VERSION 5.7 ;
  NOWIREEXTENSIONATPIN ON ;
  DIVIDERCHAR "/" ;
  BUSBITCHARS "[]" ;
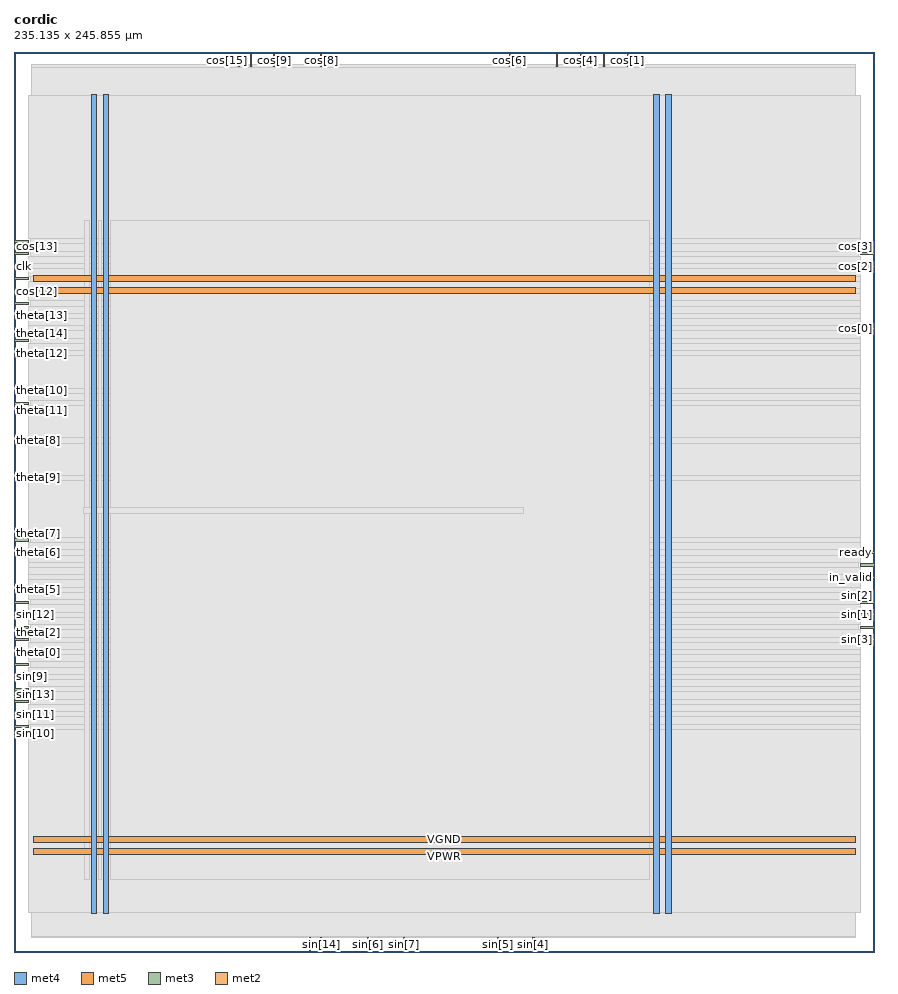
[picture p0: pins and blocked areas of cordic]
MACRO cordic
  CLASS BLOCK ;
  FOREIGN cordic ;
  ORIGIN 0.000 0.000 ;
  SIZE 235.135 BY 245.855 ;
  PIN VGND
    DIRECTION INOUT ;
    USE GROUND ;
    PORT
      LAYER met4 ;
        RECT 24.340 10.640 25.940 234.160 ;
    END
    PORT
      LAYER met4 ;
        RECT 177.940 10.640 179.540 234.160 ;
    END
    PORT
      LAYER met5 ;
        RECT 5.280 30.030 229.780 31.630 ;
    END
    PORT
      LAYER met5 ;
        RECT 5.280 183.210 229.780 184.810 ;
    END
  END VGND
  PIN VPWR
    DIRECTION INOUT ;
    USE POWER ;
    PORT
      LAYER met4 ;
        RECT 21.040 10.640 22.640 234.160 ;
    END
    PORT
      LAYER met4 ;
        RECT 174.640 10.640 176.240 234.160 ;
    END
    PORT
      LAYER met5 ;
        RECT 5.280 26.730 229.780 28.330 ;
    END
    PORT
      LAYER met5 ;
        RECT 5.280 179.910 229.780 181.510 ;
    END
  END VPWR
  PIN clk
    DIRECTION INPUT ;
    USE SIGNAL ;
    ANTENNAGATEAREA 0.852000 ;
    PORT
      LAYER met3 ;
        RECT 0.000 187.040 4.000 187.640 ;
    END
  END clk
  PIN cos[0]
    DIRECTION OUTPUT ;
    USE SIGNAL ;
    ANTENNADIFFAREA 0.795200 ;
    PORT
      LAYER met3 ;
        RECT 231.135 170.040 235.135 170.640 ;
    END
  END cos[0]
  PIN cos[10]
    DIRECTION OUTPUT ;
    USE SIGNAL ;
    ANTENNADIFFAREA 0.795200 ;
    PORT
      LAYER met2 ;
        RECT 64.490 241.855 64.770 245.855 ;
    END
  END cos[10]
  PIN cos[11]
    DIRECTION OUTPUT ;
    USE SIGNAL ;
    ANTENNADIFFAREA 0.795200 ;
    PORT
      LAYER met2 ;
        RECT 61.270 241.855 61.550 245.855 ;
    END
  END cos[11]
  PIN cos[12]
    DIRECTION OUTPUT ;
    USE SIGNAL ;
    ANTENNADIFFAREA 0.795200 ;
    PORT
      LAYER met3 ;
        RECT 0.000 180.240 4.000 180.840 ;
    END
  END cos[12]
  PIN cos[13]
    DIRECTION OUTPUT ;
    USE SIGNAL ;
    ANTENNADIFFAREA 0.795200 ;
    PORT
      LAYER met3 ;
        RECT 0.000 190.440 4.000 191.040 ;
    END
  END cos[13]
  PIN cos[14]
    DIRECTION OUTPUT ;
    USE SIGNAL ;
    ANTENNADIFFAREA 0.795200 ;
    PORT
      LAYER met3 ;
        RECT 0.000 193.840 4.000 194.440 ;
    END
  END cos[14]
  PIN cos[15]
    DIRECTION OUTPUT ;
    USE SIGNAL ;
    ANTENNADIFFAREA 0.795200 ;
    PORT
      LAYER met2 ;
        RECT 58.050 241.855 58.330 245.855 ;
    END
  END cos[15]
  PIN cos[1]
    DIRECTION OUTPUT ;
    USE SIGNAL ;
    ANTENNADIFFAREA 0.795200 ;
    PORT
      LAYER met2 ;
        RECT 167.530 241.855 167.810 245.855 ;
    END
  END cos[1]
  PIN cos[2]
    DIRECTION OUTPUT ;
    USE SIGNAL ;
    ANTENNADIFFAREA 0.795200 ;
    PORT
      LAYER met3 ;
        RECT 231.135 187.040 235.135 187.640 ;
    END
  END cos[2]
  PIN cos[3]
    DIRECTION OUTPUT ;
    USE SIGNAL ;
    ANTENNADIFFAREA 0.795200 ;
    PORT
      LAYER met3 ;
        RECT 231.135 190.440 235.135 191.040 ;
    END
  END cos[3]
  PIN cos[4]
    DIRECTION OUTPUT ;
    USE SIGNAL ;
    ANTENNADIFFAREA 0.795200 ;
    PORT
      LAYER met2 ;
        RECT 154.650 241.855 154.930 245.855 ;
    END
  END cos[4]
  PIN cos[5]
    DIRECTION OUTPUT ;
    USE SIGNAL ;
    ANTENNADIFFAREA 0.795200 ;
    PORT
      LAYER met2 ;
        RECT 161.090 241.855 161.370 245.855 ;
    END
  END cos[5]
  PIN cos[6]
    DIRECTION OUTPUT ;
    USE SIGNAL ;
    ANTENNADIFFAREA 0.795200 ;
    PORT
      LAYER met2 ;
        RECT 135.330 241.855 135.610 245.855 ;
    END
  END cos[6]
  PIN cos[7]
    DIRECTION OUTPUT ;
    USE SIGNAL ;
    ANTENNADIFFAREA 0.795200 ;
    PORT
      LAYER met2 ;
        RECT 148.210 241.855 148.490 245.855 ;
    END
  END cos[7]
  PIN cos[8]
    DIRECTION OUTPUT ;
    USE SIGNAL ;
    ANTENNADIFFAREA 0.795200 ;
    PORT
      LAYER met2 ;
        RECT 83.810 241.855 84.090 245.855 ;
    END
  END cos[8]
  PIN cos[9]
    DIRECTION OUTPUT ;
    USE SIGNAL ;
    ANTENNADIFFAREA 0.795200 ;
    PORT
      LAYER met2 ;
        RECT 70.930 241.855 71.210 245.855 ;
    END
  END cos[9]
  PIN in_valid
    DIRECTION INPUT ;
    USE SIGNAL ;
    ANTENNAGATEAREA 0.196500 ;
    PORT
      LAYER met3 ;
        RECT 231.135 102.040 235.135 102.640 ;
    END
  END in_valid
  PIN out_valid
    DIRECTION OUTPUT ;
    USE SIGNAL ;
    ANTENNADIFFAREA 0.795200 ;
    PORT
      LAYER met3 ;
        RECT 231.135 105.440 235.135 106.040 ;
    END
  END out_valid
  PIN ready
    DIRECTION OUTPUT ;
    USE SIGNAL ;
    ANTENNADIFFAREA 0.795200 ;
    PORT
      LAYER met3 ;
        RECT 231.135 108.840 235.135 109.440 ;
    END
  END ready
  PIN rstb
    DIRECTION INPUT ;
    USE SIGNAL ;
    ANTENNAGATEAREA 0.159000 ;
    PORT
      LAYER met3 ;
        RECT 0.000 183.640 4.000 184.240 ;
    END
  END rstb
  PIN sin[0]
    DIRECTION OUTPUT ;
    USE SIGNAL ;
    ANTENNADIFFAREA 0.795200 ;
    PORT
      LAYER met3 ;
        RECT 231.135 88.440 235.135 89.040 ;
    END
  END sin[0]
  PIN sin[10]
    DIRECTION OUTPUT ;
    USE SIGNAL ;
    ANTENNADIFFAREA 0.795200 ;
    PORT
      LAYER met3 ;
        RECT 0.000 61.240 4.000 61.840 ;
    END
  END sin[10]
  PIN sin[11]
    DIRECTION OUTPUT ;
    USE SIGNAL ;
    ANTENNADIFFAREA 0.795200 ;
    PORT
      LAYER met3 ;
        RECT 0.000 64.640 4.000 65.240 ;
    END
  END sin[11]
  PIN sin[12]
    DIRECTION OUTPUT ;
    USE SIGNAL ;
    ANTENNADIFFAREA 0.795200 ;
    PORT
      LAYER met3 ;
        RECT 0.000 91.840 4.000 92.440 ;
    END
  END sin[12]
  PIN sin[13]
    DIRECTION OUTPUT ;
    USE SIGNAL ;
    ANTENNADIFFAREA 0.795200 ;
    PORT
      LAYER met3 ;
        RECT 0.000 68.040 4.000 68.640 ;
    END
  END sin[13]
  PIN sin[14]
    DIRECTION OUTPUT ;
    USE SIGNAL ;
    ANTENNADIFFAREA 0.795200 ;
    PORT
      LAYER met2 ;
        RECT 83.810 0.000 84.090 4.000 ;
    END
  END sin[14]
  PIN sin[15]
    DIRECTION OUTPUT ;
    USE SIGNAL ;
    ANTENNADIFFAREA 0.795200 ;
    PORT
      LAYER met2 ;
        RECT 80.590 0.000 80.870 4.000 ;
    END
  END sin[15]
  PIN sin[1]
    DIRECTION OUTPUT ;
    USE SIGNAL ;
    ANTENNADIFFAREA 0.795200 ;
    PORT
      LAYER met3 ;
        RECT 231.135 91.840 235.135 92.440 ;
    END
  END sin[1]
  PIN sin[2]
    DIRECTION OUTPUT ;
    USE SIGNAL ;
    ANTENNADIFFAREA 0.795200 ;
    PORT
      LAYER met3 ;
        RECT 231.135 95.240 235.135 95.840 ;
    END
  END sin[2]
  PIN sin[3]
    DIRECTION OUTPUT ;
    USE SIGNAL ;
    ANTENNADIFFAREA 0.795200 ;
    PORT
      LAYER met3 ;
        RECT 231.135 85.040 235.135 85.640 ;
    END
  END sin[3]
  PIN sin[4]
    DIRECTION OUTPUT ;
    USE SIGNAL ;
    ANTENNADIFFAREA 0.795200 ;
    PORT
      LAYER met2 ;
        RECT 141.770 0.000 142.050 4.000 ;
    END
  END sin[4]
  PIN sin[5]
    DIRECTION OUTPUT ;
    USE SIGNAL ;
    ANTENNADIFFAREA 0.795200 ;
    PORT
      LAYER met2 ;
        RECT 132.110 0.000 132.390 4.000 ;
    END
  END sin[5]
  PIN sin[6]
    DIRECTION OUTPUT ;
    USE SIGNAL ;
    ANTENNADIFFAREA 0.795200 ;
    PORT
      LAYER met2 ;
        RECT 96.690 0.000 96.970 4.000 ;
    END
  END sin[6]
  PIN sin[7]
    DIRECTION OUTPUT ;
    USE SIGNAL ;
    ANTENNADIFFAREA 0.795200 ;
    PORT
      LAYER met2 ;
        RECT 106.350 0.000 106.630 4.000 ;
    END
  END sin[7]
  PIN sin[8]
    DIRECTION OUTPUT ;
    USE SIGNAL ;
    ANTENNADIFFAREA 0.795200 ;
    PORT
      LAYER met3 ;
        RECT 0.000 71.440 4.000 72.040 ;
    END
  END sin[8]
  PIN sin[9]
    DIRECTION OUTPUT ;
    USE SIGNAL ;
    ANTENNADIFFAREA 0.795200 ;
    PORT
      LAYER met3 ;
        RECT 0.000 74.840 4.000 75.440 ;
    END
  END sin[9]
  PIN theta[0]
    DIRECTION INPUT ;
    USE SIGNAL ;
    ANTENNAGATEAREA 0.196500 ;
    PORT
      LAYER met3 ;
        RECT 0.000 81.640 4.000 82.240 ;
    END
  END theta[0]
  PIN theta[10]
    DIRECTION INPUT ;
    USE SIGNAL ;
    ANTENNAGATEAREA 0.196500 ;
    PORT
      LAYER met3 ;
        RECT 0.000 153.040 4.000 153.640 ;
    END
  END theta[10]
  PIN theta[11]
    DIRECTION INPUT ;
    USE SIGNAL ;
    ANTENNAGATEAREA 0.196500 ;
    PORT
      LAYER met3 ;
        RECT 0.000 149.640 4.000 150.240 ;
    END
  END theta[11]
  PIN theta[12]
    DIRECTION INPUT ;
    USE SIGNAL ;
    ANTENNAGATEAREA 0.196500 ;
    PORT
      LAYER met3 ;
        RECT 0.000 163.240 4.000 163.840 ;
    END
  END theta[12]
  PIN theta[13]
    DIRECTION INPUT ;
    USE SIGNAL ;
    ANTENNAGATEAREA 0.196500 ;
    PORT
      LAYER met3 ;
        RECT 0.000 173.440 4.000 174.040 ;
    END
  END theta[13]
  PIN theta[14]
    DIRECTION INPUT ;
    USE SIGNAL ;
    ANTENNAGATEAREA 0.196500 ;
    PORT
      LAYER met3 ;
        RECT 0.000 166.640 4.000 167.240 ;
    END
  END theta[14]
  PIN theta[15]
    DIRECTION INPUT ;
    USE SIGNAL ;
    ANTENNAGATEAREA 0.196500 ;
    PORT
      LAYER met3 ;
        RECT 0.000 176.840 4.000 177.440 ;
    END
  END theta[15]
  PIN theta[1]
    DIRECTION INPUT ;
    USE SIGNAL ;
    ANTENNAGATEAREA 0.196500 ;
    PORT
      LAYER met3 ;
        RECT 0.000 78.240 4.000 78.840 ;
    END
  END theta[1]
  PIN theta[2]
    DIRECTION INPUT ;
    USE SIGNAL ;
    ANTENNAGATEAREA 0.196500 ;
    PORT
      LAYER met3 ;
        RECT 0.000 85.040 4.000 85.640 ;
    END
  END theta[2]
  PIN theta[3]
    DIRECTION INPUT ;
    USE SIGNAL ;
    ANTENNAGATEAREA 0.196500 ;
    PORT
      LAYER met3 ;
        RECT 0.000 88.440 4.000 89.040 ;
    END
  END theta[3]
  PIN theta[4]
    DIRECTION INPUT ;
    USE SIGNAL ;
    ANTENNAGATEAREA 0.196500 ;
    PORT
      LAYER met3 ;
        RECT 0.000 95.240 4.000 95.840 ;
    END
  END theta[4]
  PIN theta[5]
    DIRECTION INPUT ;
    USE SIGNAL ;
    ANTENNAGATEAREA 0.196500 ;
    PORT
      LAYER met3 ;
        RECT 0.000 98.640 4.000 99.240 ;
    END
  END theta[5]
  PIN theta[6]
    DIRECTION INPUT ;
    USE SIGNAL ;
    ANTENNAGATEAREA 0.196500 ;
    PORT
      LAYER met3 ;
        RECT 0.000 108.840 4.000 109.440 ;
    END
  END theta[6]
  PIN theta[7]
    DIRECTION INPUT ;
    USE SIGNAL ;
    ANTENNAGATEAREA 0.196500 ;
    PORT
      LAYER met3 ;
        RECT 0.000 112.240 4.000 112.840 ;
    END
  END theta[7]
  PIN theta[8]
    DIRECTION INPUT ;
    USE SIGNAL ;
    ANTENNAGATEAREA 0.196500 ;
    PORT
      LAYER met3 ;
        RECT 0.000 139.440 4.000 140.040 ;
    END
  END theta[8]
  PIN theta[9]
    DIRECTION INPUT ;
    USE SIGNAL ;
    ANTENNAGATEAREA 0.196500 ;
    PORT
      LAYER met3 ;
        RECT 0.000 129.240 4.000 129.840 ;
    END
  END theta[9]
  OBS
      LAYER li1 ;
        RECT 5.520 10.795 229.540 234.005 ;
      LAYER met1 ;
        RECT 4.670 10.640 229.930 234.560 ;
      LAYER met2 ;
        RECT 4.690 241.575 57.770 242.490 ;
        RECT 58.610 241.575 60.990 242.490 ;
        RECT 61.830 241.575 64.210 242.490 ;
        RECT 65.050 241.575 70.650 242.490 ;
        RECT 71.490 241.575 83.530 242.490 ;
        RECT 84.370 241.575 135.050 242.490 ;
        RECT 135.890 241.575 147.930 242.490 ;
        RECT 148.770 241.575 154.370 242.490 ;
        RECT 155.210 241.575 160.810 242.490 ;
        RECT 161.650 241.575 167.250 242.490 ;
        RECT 168.090 241.575 229.910 242.490 ;
        RECT 4.690 4.280 229.910 241.575 ;
        RECT 4.690 4.000 80.310 4.280 ;
        RECT 81.150 4.000 83.530 4.280 ;
        RECT 84.370 4.000 96.410 4.280 ;
        RECT 97.250 4.000 106.070 4.280 ;
        RECT 106.910 4.000 131.830 4.280 ;
        RECT 132.670 4.000 141.490 4.280 ;
        RECT 142.330 4.000 229.910 4.280 ;
      LAYER met3 ;
        RECT 3.990 194.840 231.135 234.085 ;
        RECT 4.400 193.440 231.135 194.840 ;
        RECT 3.990 191.440 231.135 193.440 ;
        RECT 4.400 190.040 230.735 191.440 ;
        RECT 3.990 188.040 231.135 190.040 ;
        RECT 4.400 186.640 230.735 188.040 ;
        RECT 3.990 184.640 231.135 186.640 ;
        RECT 4.400 183.240 231.135 184.640 ;
        RECT 3.990 181.240 231.135 183.240 ;
        RECT 4.400 179.840 231.135 181.240 ;
        RECT 3.990 177.840 231.135 179.840 ;
        RECT 4.400 176.440 231.135 177.840 ;
        RECT 3.990 174.440 231.135 176.440 ;
        RECT 4.400 173.040 231.135 174.440 ;
        RECT 3.990 171.040 231.135 173.040 ;
        RECT 3.990 169.640 230.735 171.040 ;
        RECT 3.990 167.640 231.135 169.640 ;
        RECT 4.400 166.240 231.135 167.640 ;
        RECT 3.990 164.240 231.135 166.240 ;
        RECT 4.400 162.840 231.135 164.240 ;
        RECT 3.990 154.040 231.135 162.840 ;
        RECT 4.400 152.640 231.135 154.040 ;
        RECT 3.990 150.640 231.135 152.640 ;
        RECT 4.400 149.240 231.135 150.640 ;
        RECT 3.990 140.440 231.135 149.240 ;
        RECT 4.400 139.040 231.135 140.440 ;
        RECT 3.990 130.240 231.135 139.040 ;
        RECT 4.400 128.840 231.135 130.240 ;
        RECT 3.990 113.240 231.135 128.840 ;
        RECT 4.400 111.840 231.135 113.240 ;
        RECT 3.990 109.840 231.135 111.840 ;
        RECT 4.400 108.440 230.735 109.840 ;
        RECT 3.990 106.440 231.135 108.440 ;
        RECT 3.990 105.040 230.735 106.440 ;
        RECT 3.990 103.040 231.135 105.040 ;
        RECT 3.990 101.640 230.735 103.040 ;
        RECT 3.990 99.640 231.135 101.640 ;
        RECT 4.400 98.240 231.135 99.640 ;
        RECT 3.990 96.240 231.135 98.240 ;
        RECT 4.400 94.840 230.735 96.240 ;
        RECT 3.990 92.840 231.135 94.840 ;
        RECT 4.400 91.440 230.735 92.840 ;
        RECT 3.990 89.440 231.135 91.440 ;
        RECT 4.400 88.040 230.735 89.440 ;
        RECT 3.990 86.040 231.135 88.040 ;
        RECT 4.400 84.640 230.735 86.040 ;
        RECT 3.990 82.640 231.135 84.640 ;
        RECT 4.400 81.240 231.135 82.640 ;
        RECT 3.990 79.240 231.135 81.240 ;
        RECT 4.400 77.840 231.135 79.240 ;
        RECT 3.990 75.840 231.135 77.840 ;
        RECT 4.400 74.440 231.135 75.840 ;
        RECT 3.990 72.440 231.135 74.440 ;
        RECT 4.400 71.040 231.135 72.440 ;
        RECT 3.990 69.040 231.135 71.040 ;
        RECT 4.400 67.640 231.135 69.040 ;
        RECT 3.990 65.640 231.135 67.640 ;
        RECT 4.400 64.240 231.135 65.640 ;
        RECT 3.990 62.240 231.135 64.240 ;
        RECT 4.400 60.840 231.135 62.240 ;
        RECT 3.990 10.715 231.135 60.840 ;
      LAYER met4 ;
        RECT 19.190 19.895 20.640 199.745 ;
        RECT 23.040 19.895 23.940 199.745 ;
        RECT 26.340 19.895 173.585 199.745 ;
      LAYER met5 ;
        RECT 18.980 119.900 139.260 121.500 ;
  END
END cordic
END LIBRARY

